One B-rep face of a CAD part: STEP entity #183.
In plain terms, the planar face has unit normal (0, -1, 0).
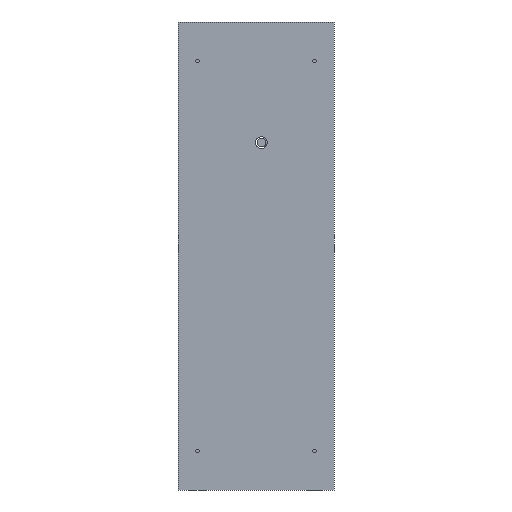
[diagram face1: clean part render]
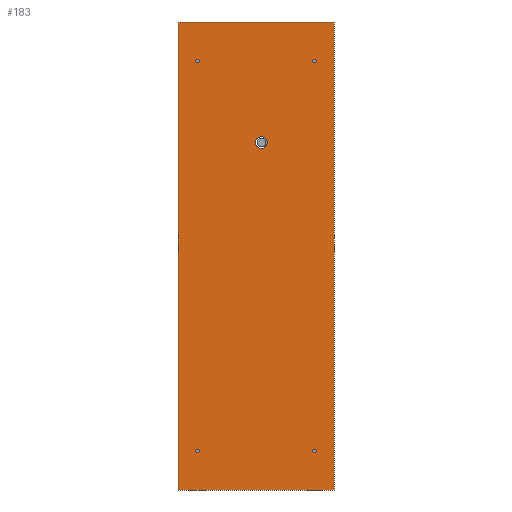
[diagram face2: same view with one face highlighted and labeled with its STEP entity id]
Its self-contained STEP definition (entity closure, numbers rounded to 3 decimals):
#67 = EDGE_CURVE('',#68,#70,#72,.T.);
#68 = VERTEX_POINT('',#69);
#69 = CARTESIAN_POINT('',(-100.,-52.,12.));
#70 = VERTEX_POINT('',#71);
#71 = CARTESIAN_POINT('',(-100.,-52.,612.));
#72 = SURFACE_CURVE('',#73,(#77,#89),.PCURVE_S1.);
#73 = LINE('',#74,#75);
#74 = CARTESIAN_POINT('',(-100.,-52.,12.));
#75 = VECTOR('',#76,1.);
#76 = DIRECTION('',(0.,0.,1.));
#77 = PCURVE('',#78,#83);
#78 = PLANE('',#79);
#79 = AXIS2_PLACEMENT_3D('',#80,#81,#82);
#80 = CARTESIAN_POINT('',(-100.,-52.,12.));
#81 = DIRECTION('',(1.,0.,0.));
#82 = DIRECTION('',(0.,0.,1.));
#83 = DEFINITIONAL_REPRESENTATION('',(#84),#88);
#84 = LINE('',#85,#86);
#85 = CARTESIAN_POINT('',(0.,0.));
#86 = VECTOR('',#87,1.);
#87 = DIRECTION('',(1.,0.));
#88 = ( GEOMETRIC_REPRESENTATION_CONTEXT(2) 
PARAMETRIC_REPRESENTATION_CONTEXT() REPRESENTATION_CONTEXT('2D SPACE',''
  ) );
#89 = PCURVE('',#90,#95);
#90 = PLANE('',#91);
#91 = AXIS2_PLACEMENT_3D('',#92,#93,#94);
#92 = CARTESIAN_POINT('',(-100.,-52.,12.));
#93 = DIRECTION('',(0.,1.,0.));
#94 = DIRECTION('',(0.,0.,1.));
#95 = DEFINITIONAL_REPRESENTATION('',(#96),#100);
#96 = LINE('',#97,#98);
#97 = CARTESIAN_POINT('',(0.,0.));
#98 = VECTOR('',#99,1.);
#99 = DIRECTION('',(1.,0.));
#100 = ( GEOMETRIC_REPRESENTATION_CONTEXT(2) 
PARAMETRIC_REPRESENTATION_CONTEXT() REPRESENTATION_CONTEXT('2D SPACE',''
  ) );
#118 = PLANE('',#119);
#119 = AXIS2_PLACEMENT_3D('',#120,#121,#122);
#120 = CARTESIAN_POINT('',(-100.,-52.,12.));
#121 = DIRECTION('',(0.,0.,1.));
#122 = DIRECTION('',(1.,0.,0.));
#172 = PLANE('',#173);
#173 = AXIS2_PLACEMENT_3D('',#174,#175,#176);
#174 = CARTESIAN_POINT('',(-100.,-52.,612.));
#175 = DIRECTION('',(0.,0.,1.));
#176 = DIRECTION('',(1.,0.,0.));
#183 = ADVANCED_FACE('',(#184,#259,#290,#321,#352,#383),#90,.F.);
#184 = FACE_BOUND('',#185,.F.);
#185 = EDGE_LOOP('',(#186,#209,#210,#233));
#186 = ORIENTED_EDGE('',*,*,#187,.F.);
#187 = EDGE_CURVE('',#68,#188,#190,.T.);
#188 = VERTEX_POINT('',#189);
#189 = CARTESIAN_POINT('',(100.,-52.,12.));
#190 = SURFACE_CURVE('',#191,(#195,#202),.PCURVE_S1.);
#191 = LINE('',#192,#193);
#192 = CARTESIAN_POINT('',(-100.,-52.,12.));
#193 = VECTOR('',#194,1.);
#194 = DIRECTION('',(1.,0.,0.));
#195 = PCURVE('',#90,#196);
#196 = DEFINITIONAL_REPRESENTATION('',(#197),#201);
#197 = LINE('',#198,#199);
#198 = CARTESIAN_POINT('',(0.,0.));
#199 = VECTOR('',#200,1.);
#200 = DIRECTION('',(0.,1.));
#201 = ( GEOMETRIC_REPRESENTATION_CONTEXT(2) 
PARAMETRIC_REPRESENTATION_CONTEXT() REPRESENTATION_CONTEXT('2D SPACE',''
  ) );
#202 = PCURVE('',#118,#203);
#203 = DEFINITIONAL_REPRESENTATION('',(#204),#208);
#204 = LINE('',#205,#206);
#205 = CARTESIAN_POINT('',(0.,0.));
#206 = VECTOR('',#207,1.);
#207 = DIRECTION('',(1.,0.));
#208 = ( GEOMETRIC_REPRESENTATION_CONTEXT(2) 
PARAMETRIC_REPRESENTATION_CONTEXT() REPRESENTATION_CONTEXT('2D SPACE',''
  ) );
#209 = ORIENTED_EDGE('',*,*,#67,.T.);
#210 = ORIENTED_EDGE('',*,*,#211,.T.);
#211 = EDGE_CURVE('',#70,#212,#214,.T.);
#212 = VERTEX_POINT('',#213);
#213 = CARTESIAN_POINT('',(100.,-52.,612.));
#214 = SURFACE_CURVE('',#215,(#219,#226),.PCURVE_S1.);
#215 = LINE('',#216,#217);
#216 = CARTESIAN_POINT('',(-100.,-52.,612.));
#217 = VECTOR('',#218,1.);
#218 = DIRECTION('',(1.,0.,0.));
#219 = PCURVE('',#90,#220);
#220 = DEFINITIONAL_REPRESENTATION('',(#221),#225);
#221 = LINE('',#222,#223);
#222 = CARTESIAN_POINT('',(600.,0.));
#223 = VECTOR('',#224,1.);
#224 = DIRECTION('',(0.,1.));
#225 = ( GEOMETRIC_REPRESENTATION_CONTEXT(2) 
PARAMETRIC_REPRESENTATION_CONTEXT() REPRESENTATION_CONTEXT('2D SPACE',''
  ) );
#226 = PCURVE('',#172,#227);
#227 = DEFINITIONAL_REPRESENTATION('',(#228),#232);
#228 = LINE('',#229,#230);
#229 = CARTESIAN_POINT('',(0.,0.));
#230 = VECTOR('',#231,1.);
#231 = DIRECTION('',(1.,0.));
#232 = ( GEOMETRIC_REPRESENTATION_CONTEXT(2) 
PARAMETRIC_REPRESENTATION_CONTEXT() REPRESENTATION_CONTEXT('2D SPACE',''
  ) );
#233 = ORIENTED_EDGE('',*,*,#234,.F.);
#234 = EDGE_CURVE('',#188,#212,#235,.T.);
#235 = SURFACE_CURVE('',#236,(#240,#247),.PCURVE_S1.);
#236 = LINE('',#237,#238);
#237 = CARTESIAN_POINT('',(100.,-52.,12.));
#238 = VECTOR('',#239,1.);
#239 = DIRECTION('',(0.,0.,1.));
#240 = PCURVE('',#90,#241);
#241 = DEFINITIONAL_REPRESENTATION('',(#242),#246);
#242 = LINE('',#243,#244);
#243 = CARTESIAN_POINT('',(0.,200.));
#244 = VECTOR('',#245,1.);
#245 = DIRECTION('',(1.,0.));
#246 = ( GEOMETRIC_REPRESENTATION_CONTEXT(2) 
PARAMETRIC_REPRESENTATION_CONTEXT() REPRESENTATION_CONTEXT('2D SPACE',''
  ) );
#247 = PCURVE('',#248,#253);
#248 = PLANE('',#249);
#249 = AXIS2_PLACEMENT_3D('',#250,#251,#252);
#250 = CARTESIAN_POINT('',(100.,-52.,12.));
#251 = DIRECTION('',(1.,0.,0.));
#252 = DIRECTION('',(0.,0.,1.));
#253 = DEFINITIONAL_REPRESENTATION('',(#254),#258);
#254 = LINE('',#255,#256);
#255 = CARTESIAN_POINT('',(0.,0.));
#256 = VECTOR('',#257,1.);
#257 = DIRECTION('',(1.,0.));
#258 = ( GEOMETRIC_REPRESENTATION_CONTEXT(2) 
PARAMETRIC_REPRESENTATION_CONTEXT() REPRESENTATION_CONTEXT('2D SPACE',''
  ) );
#259 = FACE_BOUND('',#260,.F.);
#260 = EDGE_LOOP('',(#261));
#261 = ORIENTED_EDGE('',*,*,#262,.F.);
#262 = EDGE_CURVE('',#263,#263,#265,.T.);
#263 = VERTEX_POINT('',#264);
#264 = CARTESIAN_POINT('',(-75.,-52.,64.25));
#265 = SURFACE_CURVE('',#266,(#271,#278),.PCURVE_S1.);
#266 = CIRCLE('',#267,2.25);
#267 = AXIS2_PLACEMENT_3D('',#268,#269,#270);
#268 = CARTESIAN_POINT('',(-75.,-52.,62.));
#269 = DIRECTION('',(0.,1.,0.));
#270 = DIRECTION('',(0.,-0.,1.));
#271 = PCURVE('',#90,#272);
#272 = DEFINITIONAL_REPRESENTATION('',(#273),#277);
#273 = CIRCLE('',#274,2.25);
#274 = AXIS2_PLACEMENT_2D('',#275,#276);
#275 = CARTESIAN_POINT('',(50.,25.));
#276 = DIRECTION('',(1.,0.));
#277 = ( GEOMETRIC_REPRESENTATION_CONTEXT(2) 
PARAMETRIC_REPRESENTATION_CONTEXT() REPRESENTATION_CONTEXT('2D SPACE',''
  ) );
#278 = PCURVE('',#279,#284);
#279 = CYLINDRICAL_SURFACE('',#280,2.25);
#280 = AXIS2_PLACEMENT_3D('',#281,#282,#283);
#281 = CARTESIAN_POINT('',(-75.,-52.,62.));
#282 = DIRECTION('',(0.,1.,0.));
#283 = DIRECTION('',(0.,-0.,1.));
#284 = DEFINITIONAL_REPRESENTATION('',(#285),#289);
#285 = LINE('',#286,#287);
#286 = CARTESIAN_POINT('',(0.,0.));
#287 = VECTOR('',#288,1.);
#288 = DIRECTION('',(1.,0.));
#289 = ( GEOMETRIC_REPRESENTATION_CONTEXT(2) 
PARAMETRIC_REPRESENTATION_CONTEXT() REPRESENTATION_CONTEXT('2D SPACE',''
  ) );
#290 = FACE_BOUND('',#291,.F.);
#291 = EDGE_LOOP('',(#292));
#292 = ORIENTED_EDGE('',*,*,#293,.F.);
#293 = EDGE_CURVE('',#294,#294,#296,.T.);
#294 = VERTEX_POINT('',#295);
#295 = CARTESIAN_POINT('',(-75.,-52.,564.25));
#296 = SURFACE_CURVE('',#297,(#302,#309),.PCURVE_S1.);
#297 = CIRCLE('',#298,2.25);
#298 = AXIS2_PLACEMENT_3D('',#299,#300,#301);
#299 = CARTESIAN_POINT('',(-75.,-52.,562.));
#300 = DIRECTION('',(0.,1.,0.));
#301 = DIRECTION('',(0.,-0.,1.));
#302 = PCURVE('',#90,#303);
#303 = DEFINITIONAL_REPRESENTATION('',(#304),#308);
#304 = CIRCLE('',#305,2.25);
#305 = AXIS2_PLACEMENT_2D('',#306,#307);
#306 = CARTESIAN_POINT('',(550.,25.));
#307 = DIRECTION('',(1.,0.));
#308 = ( GEOMETRIC_REPRESENTATION_CONTEXT(2) 
PARAMETRIC_REPRESENTATION_CONTEXT() REPRESENTATION_CONTEXT('2D SPACE',''
  ) );
#309 = PCURVE('',#310,#315);
#310 = CYLINDRICAL_SURFACE('',#311,2.25);
#311 = AXIS2_PLACEMENT_3D('',#312,#313,#314);
#312 = CARTESIAN_POINT('',(-75.,-52.,562.));
#313 = DIRECTION('',(0.,1.,0.));
#314 = DIRECTION('',(0.,-0.,1.));
#315 = DEFINITIONAL_REPRESENTATION('',(#316),#320);
#316 = LINE('',#317,#318);
#317 = CARTESIAN_POINT('',(0.,0.));
#318 = VECTOR('',#319,1.);
#319 = DIRECTION('',(1.,0.));
#320 = ( GEOMETRIC_REPRESENTATION_CONTEXT(2) 
PARAMETRIC_REPRESENTATION_CONTEXT() REPRESENTATION_CONTEXT('2D SPACE',''
  ) );
#321 = FACE_BOUND('',#322,.F.);
#322 = EDGE_LOOP('',(#323));
#323 = ORIENTED_EDGE('',*,*,#324,.F.);
#324 = EDGE_CURVE('',#325,#325,#327,.T.);
#325 = VERTEX_POINT('',#326);
#326 = CARTESIAN_POINT('',(75.,-52.,64.25));
#327 = SURFACE_CURVE('',#328,(#333,#340),.PCURVE_S1.);
#328 = CIRCLE('',#329,2.25);
#329 = AXIS2_PLACEMENT_3D('',#330,#331,#332);
#330 = CARTESIAN_POINT('',(75.,-52.,62.));
#331 = DIRECTION('',(0.,1.,0.));
#332 = DIRECTION('',(0.,-0.,1.));
#333 = PCURVE('',#90,#334);
#334 = DEFINITIONAL_REPRESENTATION('',(#335),#339);
#335 = CIRCLE('',#336,2.25);
#336 = AXIS2_PLACEMENT_2D('',#337,#338);
#337 = CARTESIAN_POINT('',(50.,175.));
#338 = DIRECTION('',(1.,0.));
#339 = ( GEOMETRIC_REPRESENTATION_CONTEXT(2) 
PARAMETRIC_REPRESENTATION_CONTEXT() REPRESENTATION_CONTEXT('2D SPACE',''
  ) );
#340 = PCURVE('',#341,#346);
#341 = CYLINDRICAL_SURFACE('',#342,2.25);
#342 = AXIS2_PLACEMENT_3D('',#343,#344,#345);
#343 = CARTESIAN_POINT('',(75.,-52.,62.));
#344 = DIRECTION('',(0.,1.,0.));
#345 = DIRECTION('',(0.,-0.,1.));
#346 = DEFINITIONAL_REPRESENTATION('',(#347),#351);
#347 = LINE('',#348,#349);
#348 = CARTESIAN_POINT('',(0.,0.));
#349 = VECTOR('',#350,1.);
#350 = DIRECTION('',(1.,0.));
#351 = ( GEOMETRIC_REPRESENTATION_CONTEXT(2) 
PARAMETRIC_REPRESENTATION_CONTEXT() REPRESENTATION_CONTEXT('2D SPACE',''
  ) );
#352 = FACE_BOUND('',#353,.F.);
#353 = EDGE_LOOP('',(#354));
#354 = ORIENTED_EDGE('',*,*,#355,.F.);
#355 = EDGE_CURVE('',#356,#356,#358,.T.);
#356 = VERTEX_POINT('',#357);
#357 = CARTESIAN_POINT('',(7.,-52.,465.));
#358 = SURFACE_CURVE('',#359,(#364,#371),.PCURVE_S1.);
#359 = CIRCLE('',#360,7.5);
#360 = AXIS2_PLACEMENT_3D('',#361,#362,#363);
#361 = CARTESIAN_POINT('',(7.,-52.,457.5));
#362 = DIRECTION('',(0.,1.,0.));
#363 = DIRECTION('',(0.,-0.,1.));
#364 = PCURVE('',#90,#365);
#365 = DEFINITIONAL_REPRESENTATION('',(#366),#370);
#366 = CIRCLE('',#367,7.5);
#367 = AXIS2_PLACEMENT_2D('',#368,#369);
#368 = CARTESIAN_POINT('',(445.5,107.));
#369 = DIRECTION('',(1.,0.));
#370 = ( GEOMETRIC_REPRESENTATION_CONTEXT(2) 
PARAMETRIC_REPRESENTATION_CONTEXT() REPRESENTATION_CONTEXT('2D SPACE',''
  ) );
#371 = PCURVE('',#372,#377);
#372 = CYLINDRICAL_SURFACE('',#373,7.5);
#373 = AXIS2_PLACEMENT_3D('',#374,#375,#376);
#374 = CARTESIAN_POINT('',(7.,-52.,457.5));
#375 = DIRECTION('',(0.,1.,0.));
#376 = DIRECTION('',(0.,-0.,1.));
#377 = DEFINITIONAL_REPRESENTATION('',(#378),#382);
#378 = LINE('',#379,#380);
#379 = CARTESIAN_POINT('',(0.,0.));
#380 = VECTOR('',#381,1.);
#381 = DIRECTION('',(1.,0.));
#382 = ( GEOMETRIC_REPRESENTATION_CONTEXT(2) 
PARAMETRIC_REPRESENTATION_CONTEXT() REPRESENTATION_CONTEXT('2D SPACE',''
  ) );
#383 = FACE_BOUND('',#384,.F.);
#384 = EDGE_LOOP('',(#385));
#385 = ORIENTED_EDGE('',*,*,#386,.F.);
#386 = EDGE_CURVE('',#387,#387,#389,.T.);
#387 = VERTEX_POINT('',#388);
#388 = CARTESIAN_POINT('',(75.,-52.,564.25));
#389 = SURFACE_CURVE('',#390,(#395,#402),.PCURVE_S1.);
#390 = CIRCLE('',#391,2.25);
#391 = AXIS2_PLACEMENT_3D('',#392,#393,#394);
#392 = CARTESIAN_POINT('',(75.,-52.,562.));
#393 = DIRECTION('',(0.,1.,0.));
#394 = DIRECTION('',(0.,-0.,1.));
#395 = PCURVE('',#90,#396);
#396 = DEFINITIONAL_REPRESENTATION('',(#397),#401);
#397 = CIRCLE('',#398,2.25);
#398 = AXIS2_PLACEMENT_2D('',#399,#400);
#399 = CARTESIAN_POINT('',(550.,175.));
#400 = DIRECTION('',(1.,0.));
#401 = ( GEOMETRIC_REPRESENTATION_CONTEXT(2) 
PARAMETRIC_REPRESENTATION_CONTEXT() REPRESENTATION_CONTEXT('2D SPACE',''
  ) );
#402 = PCURVE('',#403,#408);
#403 = CYLINDRICAL_SURFACE('',#404,2.25);
#404 = AXIS2_PLACEMENT_3D('',#405,#406,#407);
#405 = CARTESIAN_POINT('',(75.,-52.,562.));
#406 = DIRECTION('',(0.,1.,0.));
#407 = DIRECTION('',(0.,-0.,1.));
#408 = DEFINITIONAL_REPRESENTATION('',(#409),#413);
#409 = LINE('',#410,#411);
#410 = CARTESIAN_POINT('',(0.,0.));
#411 = VECTOR('',#412,1.);
#412 = DIRECTION('',(1.,0.));
#413 = ( GEOMETRIC_REPRESENTATION_CONTEXT(2) 
PARAMETRIC_REPRESENTATION_CONTEXT() REPRESENTATION_CONTEXT('2D SPACE',''
  ) );
